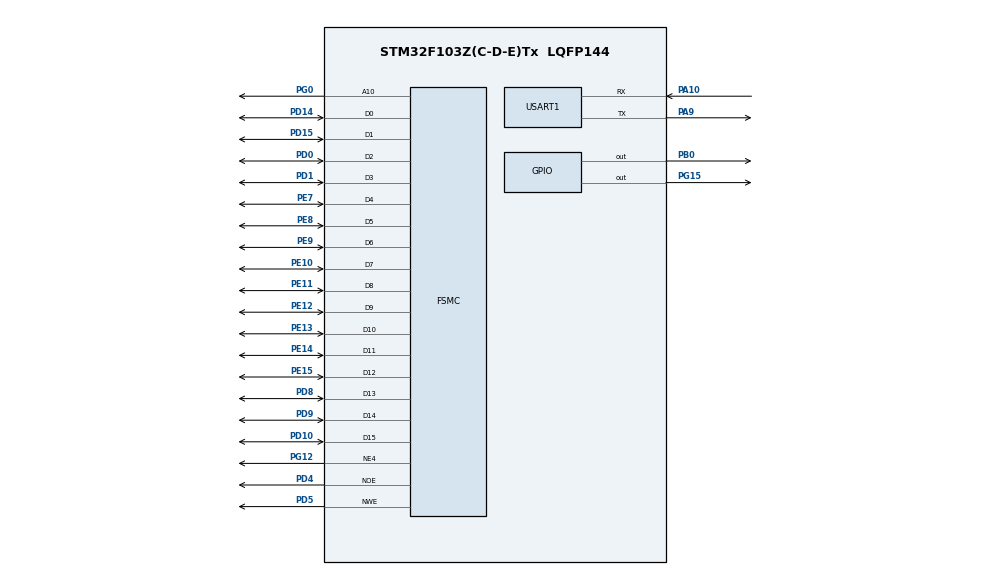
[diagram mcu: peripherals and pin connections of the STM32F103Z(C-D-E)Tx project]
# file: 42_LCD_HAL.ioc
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FSMC.DataSetupTime1=71
Mcu.Family=STM32F1
Mcu.Name=STM32F103Z(C-D-E)Tx
Mcu.Package=LQFP144
NVIC.PriorityGroup=NVIC_PRIORITYGROUP_4
OSC_IN.Mode=HSE-External-Oscillator
OSC_IN.Signal=RCC_OSC_IN
OSC_OUT.Mode=HSE-External-Oscillator
OSC_OUT.Signal=RCC_OSC_OUT
PA10.Mode=Asynchronous
PA10.Signal=USART1_RX
PA13.Mode=Serial_Wire
PA13.Signal=SYS_JTMS-SWDIO
PA14.Mode=Serial_Wire
PA14.Signal=SYS_JTCK-SWCLK
PA9.Mode=Asynchronous
PA9.Signal=USART1_TX
PB0.GPIO_Speed=GPIO_SPEED_FREQ_HIGH
PB0.Signal=GPIO_Output
PC14-OSC32_IN.Mode=LSE-External-Oscillator
PC14-OSC32_IN.Signal=RCC_OSC32_IN
PC15-OSC32_OUT.Mode=LSE-External-Oscillator
PC15-OSC32_OUT.Signal=RCC_OSC32_OUT
PD0.Signal=FSMC_D2_DA2
PD1.Signal=FSMC_D3_DA3
PD10.Signal=FSMC_D15_DA15
PD14.Signal=FSMC_D0_DA0
PD15.Signal=FSMC_D1_DA1
PD4.Signal=FSMC_NOE
PD5.Signal=FSMC_NWE
PD8.Signal=FSMC_D13_DA13
PD9.Signal=FSMC_D14_DA14
PE10.Signal=FSMC_D7_DA7
PE11.Signal=FSMC_D8_DA8
PE12.Signal=FSMC_D9_DA9
PE13.Signal=FSMC_D10_DA10
PE14.Signal=FSMC_D11_DA11
PE15.Signal=FSMC_D12_DA12
PE7.Signal=FSMC_D4_DA4
PE8.Signal=FSMC_D5_DA5
PE9.Signal=FSMC_D6_DA6
PG0.Signal=FSMC_A10
PG12.Mode=NorPsramChipSelect4_1
PG12.Signal=FSMC_NE4
PG15.GPIO_Speed=GPIO_SPEED_FREQ_HIGH
PG15.PinState=GPIO_PIN_SET
PG15.Signal=GPIO_Output
ProjectManager.HeapSize=0x200
ProjectManager.StackSize=0x400
ProjectManager.TargetToolchain=MDK-ARM V5.32
RCC.AHBFreq_Value=72000000
RCC.APB1CLKDivider=RCC_HCLK_DIV2
RCC.APB1Freq_Value=36000000
RCC.APB1TimFreq_Value=72000000
RCC.APB2Freq_Value=72000000
RCC.APB2TimFreq_Value=72000000
RCC.HCLKFreq_Value=72000000
RCC.PLLMUL=RCC_PLL_MUL9
RCC.PLLSourceVirtual=RCC_PLLSOURCE_HSE
RCC.SYSCLKFreq_VALUE=72000000
RCC.SYSCLKSource=RCC_SYSCLKSOURCE_PLLCLK
RCC.USBFreq_Value=72000000
SH.FSMC_A10.0=FSMC_A10,A10_1
SH.FSMC_D0_DA0.0=FSMC_D0,16b-d1
SH.FSMC_D10_DA10.0=FSMC_D10,16b-d1
SH.FSMC_D11_DA11.0=FSMC_D11,16b-d1
SH.FSMC_D12_DA12.0=FSMC_D12,16b-d1
SH.FSMC_D13_DA13.0=FSMC_D13,16b-d1
SH.FSMC_D14_DA14.0=FSMC_D14,16b-d1
SH.FSMC_D15_DA15.0=FSMC_D15,16b-d1
SH.FSMC_D1_DA1.0=FSMC_D1,16b-d1
SH.FSMC_D2_DA2.0=FSMC_D2,16b-d1
SH.FSMC_D3_DA3.0=FSMC_D3,16b-d1
SH.FSMC_D4_DA4.0=FSMC_D4,16b-d1
SH.FSMC_D5_DA5.0=FSMC_D5,16b-d1
SH.FSMC_D6_DA6.0=FSMC_D6,16b-d1
SH.FSMC_D7_DA7.0=FSMC_D7,16b-d1
SH.FSMC_D8_DA8.0=FSMC_D8,16b-d1
SH.FSMC_D9_DA9.0=FSMC_D9,16b-d1
SH.FSMC_NOE.0=FSMC_NOE,Lcd1
SH.FSMC_NWE.0=FSMC_NWE,Lcd1
USART1.VirtualMode=VM_ASYNC
board=custom

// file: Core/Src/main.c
/* USER CODE BEGIN Header */
/**
  ******************************************************************************
  * @file           : main.c
  * @brief          : Main program body
  ******************************************************************************
  * @attention
  *
  * Copyright (c) 2026 STMicroelectronics.
  * All rights reserved.
  *
  * This software is licensed under terms that can be found in the LICENSE file
  * in the root directory of this software component.
  * If no LICENSE file comes with this software, it is provided AS-IS.
  *
  ******************************************************************************
  */
/* USER CODE END Header */
#include "main.h"
#include "usart.h"
#include "gpio.h"
#include "fsmc.h"

/* USER CODE BEGIN Includes */
#include "lcd.h"
/* USER CODE END Includes */

void SystemClock_Config(void);

int main(void)
{

  /* MCU Configuration--------------------------------------------------------*/

  /* Reset of all peripherals, Initializes the Flash interface and the Systick. */
  HAL_Init();

  /* Configure the system clock */
  SystemClock_Config();

  /* Initialize all configured peripherals */
  MX_GPIO_Init();
  MX_FSMC_Init();
  MX_USART1_UART_Init();
  /* USER CODE BEGIN 2 */
  /* ---- LCD 最小验证：严格对齐 40_fsmc__lcd_rigister 的 main.c 顺序与内容 ----
     40 号验证正常的顺序是：
         LCD_Init(); LCD_ReadId(); LCD_BGOn(); LCD_ClearAll(WHITE); 然后画图形
     这里刻意保持完全一致，先确认"驱动层 + 时序"本身能不能正常显示，
     把 main 层的干扰因素（额外延时、坐标改动）全部剔除。
     确认能显示后，再逐步加回。*/
  LCD_Init();
  /* 降速实验期间主频只有 4MHz，LCD 上电稳定所需时间比 72MHz 下长得多，
     这里额外多等一会儿，确保屏完全就绪。72MHz 稳定后可去掉这段。 */
  HAL_Delay(500);
  volatile uint32_t id = LCD_ReadId();
  (void)id;

  LCD_BGOn();
  HAL_Delay(100);
  LCD_ClearAll(WHITE);
  HAL_Delay(200);

  /* 以下图形坐标与 40 号 main.c 完全一致，便于逐条对照显示效果 */
  LCD_DrawLine(100, 100, 200, 200, 2, RED);
  LCD_DrawCFX(0, 0, 100, 100, 2, RED);
  LCD_DrawCircle(100, 100, 50, 2, RED);
  LCD_DrawCircle_Pro(150, 150, 50, 2, RED, RED);
  /* USER CODE END 2 */

  /* Infinite loop */
  while (1)
  {

    /* USER CODE BEGIN 3 */
    /* 想验证屏幕不会"跑飞"，可以在此继续写显存，观察图形是否稳定 */
    /* USER CODE END 3 */
  }
  /* USER CODE END 3 */
}

void SystemClock_Config(void)
{
  RCC_OscInitTypeDef RCC_OscInitStruct = {0};
  RCC_ClkInitTypeDef RCC_ClkInitStruct = {0};

  /** Initializes the RCC Oscillators according to the specified parameters
  * in the RCC_OscInitTypeDef structure.
  */
  /* 【降速实验】先临时用 HSI + PLL_MUL2 = 8MHz（F1 的 PLLMUL 从 2 起，无 MUL1）。
     目的：代码侧（时序数值/引脚/逻辑）已与 40 号对齐但仍花屏，
     需要判断是"总线速度过快导致信号完整性问题"还是"代码逻辑问题"。
     若 8MHz 下显示正常 → 改用 HSE，PLLMUL 逐级升 2/3/4/6/9 找出临界点。
     若 8MHz 下依然花屏 → 彻底排除速度因素，去查 FPC 接触 / 屏模块本体。
     验证完记得改回 HSE + PLL_MUL9 = 72MHz。 */
  RCC_OscInitStruct.OscillatorType = RCC_OSCILLATORTYPE_HSI;
  RCC_OscInitStruct.HSEState = RCC_HSE_ON;
  RCC_OscInitStruct.HSEPredivValue = RCC_HSE_PREDIV_DIV1;
  RCC_OscInitStruct.HSIState = RCC_HSI_ON;
  RCC_OscInitStruct.PLL.PLLState = RCC_PLL_ON;
  RCC_OscInitStruct.PLL.PLLSource = RCC_PLLSOURCE_HSI_DIV2;
  RCC_OscInitStruct.PLL.PLLMUL = RCC_PLL_MUL2;   /* HSI 8MHz/2*2 = 8MHz */
  if (HAL_RCC_OscConfig(&RCC_OscInitStruct) != HAL_OK)
  {
    Error_Handler();
  }

  /** Initializes the CPU, AHB and APB buses clocks
  */
  RCC_ClkInitStruct.ClockType = RCC_CLOCKTYPE_HCLK|RCC_CLOCKTYPE_SYSCLK
                              |RCC_CLOCKTYPE_PCLK1|RCC_CLOCKTYPE_PCLK2;
  RCC_ClkInitStruct.SYSCLKSource = RCC_SYSCLKSOURCE_PLLCLK;
  RCC_ClkInitStruct.AHBCLKDivider = RCC_SYSCLK_DIV1;
  RCC_ClkInitStruct.APB1CLKDivider = RCC_HCLK_DIV2;
  RCC_ClkInitStruct.APB2CLKDivider = RCC_HCLK_DIV1;

  if (HAL_RCC_ClockConfig(&RCC_ClkInitStruct, FLASH_LATENCY_0) != HAL_OK)
  {
    Error_Handler();
  }
}

void Error_Handler(void)
{
  __disable_irq();
  while (1)
  {
  }
}
